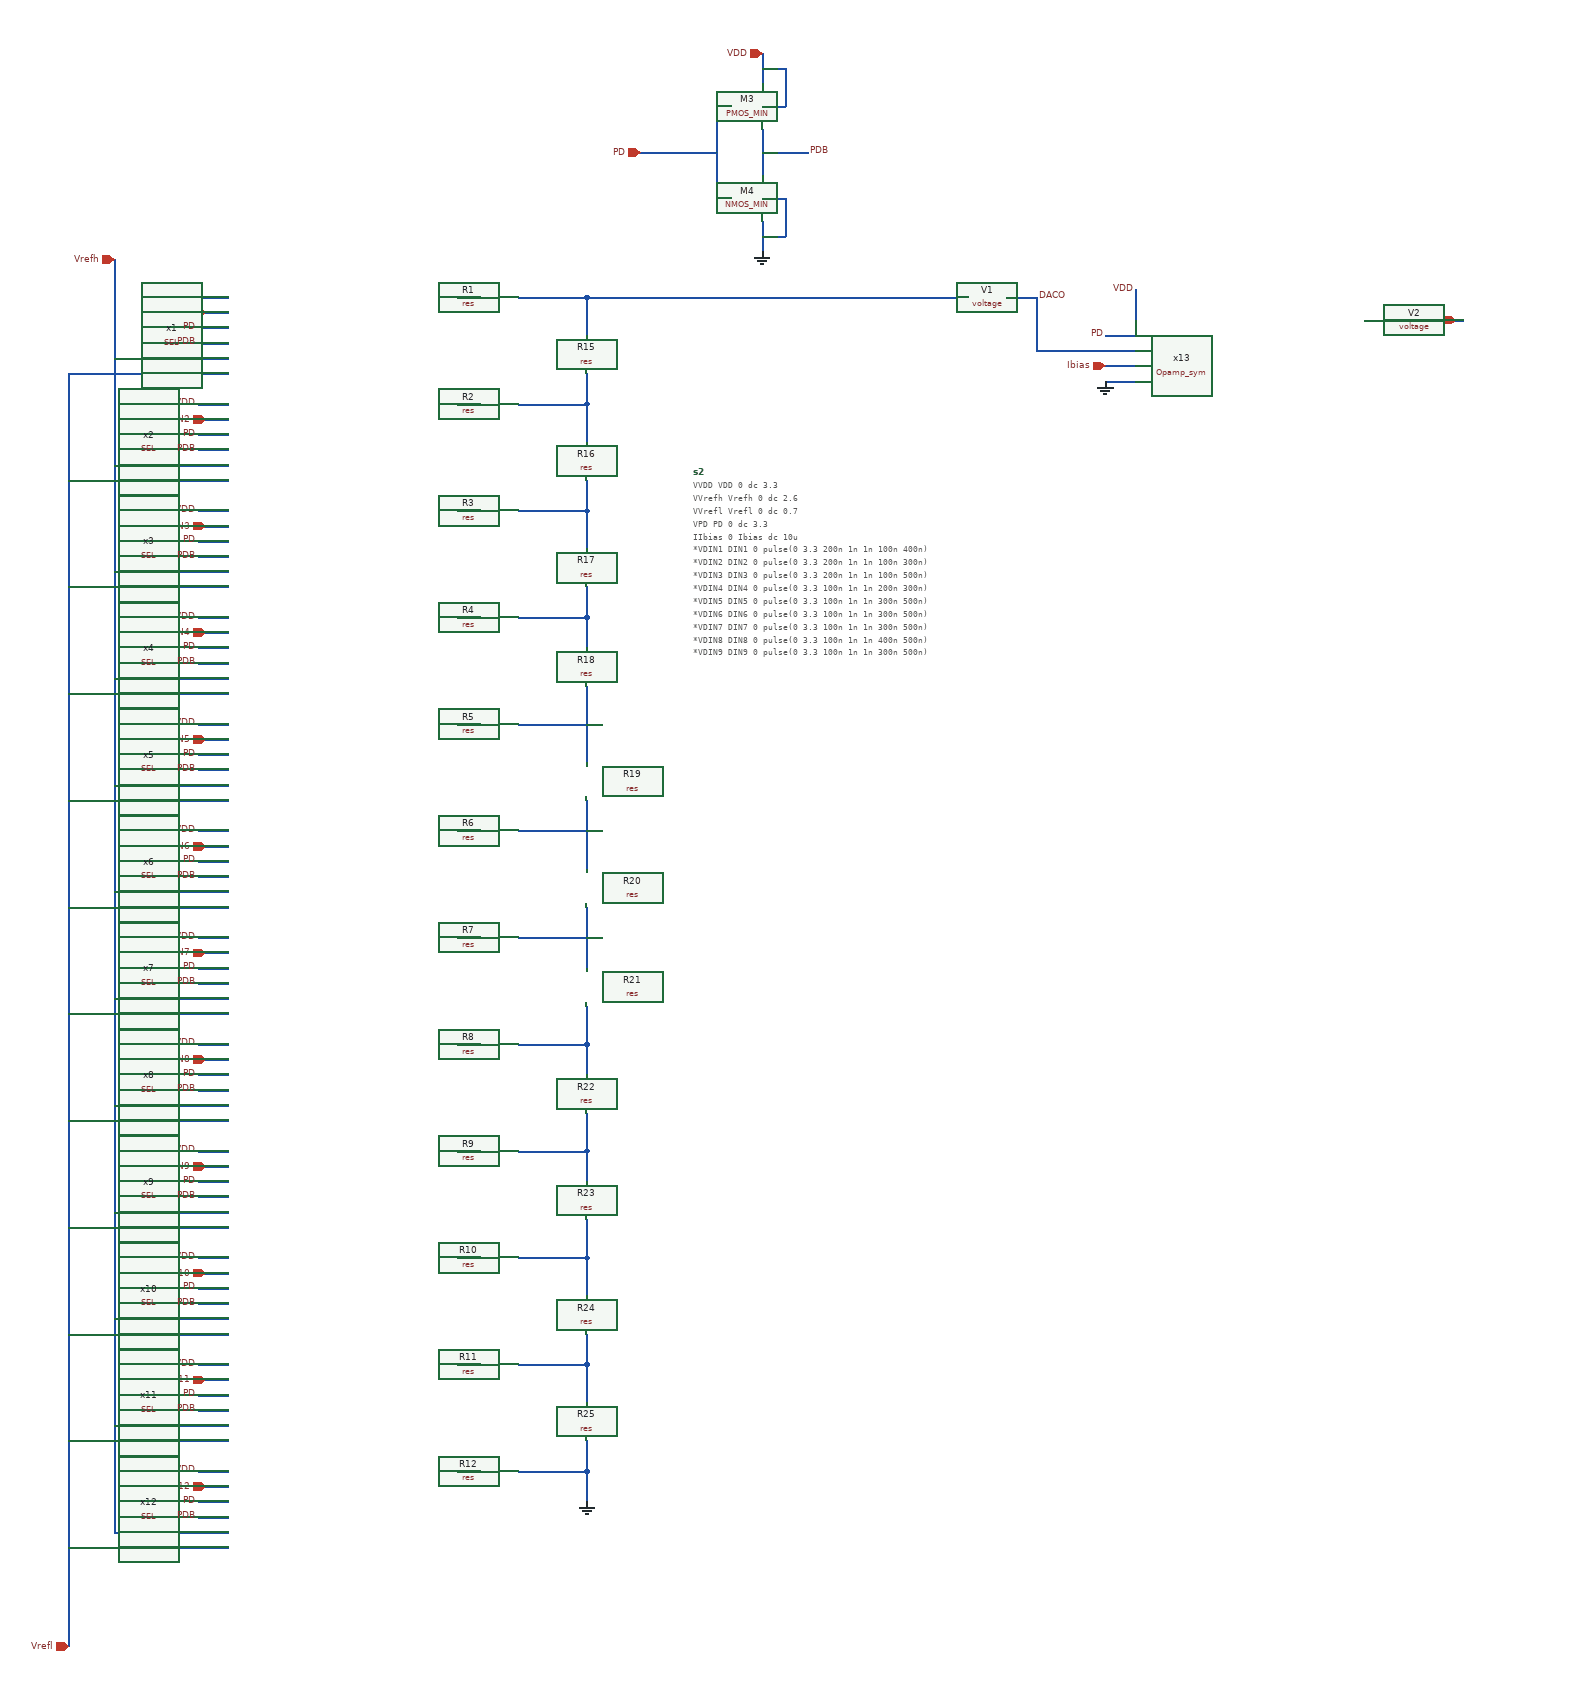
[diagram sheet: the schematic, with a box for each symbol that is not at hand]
v {xschem version=3.4.8RC file_version=1.3}
G {}
K {}
V {}
S {}
F {}
E {}
N 50 -100 140 -100 {lab=#net1}
N 50 40 140 40 {lab=#net2}
N -30 -100 -0 -100 {lab=#net3}
N -30 40 0 40 {lab=#net4}
N -30 180 0 180 {lab=#net5}
N -30 460 0 460 {lab=#net6}
N -30 320 0 320 {lab=#net7}
N -30 600 0 600 {lab=#net8}
N -30 740 0 740 {lab=#net9}
N -30 880 0 880 {lab=#net10}
N -30 1020 0 1020 {lab=#net11}
N -30 1160 0 1160 {lab=#net12}
N -30 1300 0 1300 {lab=#net13}
N -30 1440 0 1440 {lab=#net14}
N -480 -60 -480 1220 {lab=Vrefh}
N -480 1100 -340 1100 {lab=Vrefh}
N -480 260 -340 260 {lab=Vrefh}
N -540 1120 -340 1120 {lab=Vrefl}
N -540 280 -340 280 {lab=Vrefl}
N 140 -100 280 -100 {lab=#net1}
N -360 -80 -330 -80 {lab=DIN1}
N -360 60 -330 60 {lab=DIN2}
N -360 200 -330 200 {lab=DIN3}
N -360 340 -330 340 {lab=DIN4}
N -360 480 -330 480 {lab=DIN5}
N -360 620 -330 620 {lab=DIN6}
N -360 760 -330 760 {lab=DIN7}
N -360 900 -330 900 {lab=DIN8}
N -360 1040 -330 1040 {lab=DIN9}
N -360 1180 -330 1180 {lab=DIN10}
N -360 1320 -330 1320 {lab=DIN11}
N -360 1460 -330 1460 {lab=DIN12}
N 140 -100 140 -70 {lab=#net1}
N 50 180 140 180 {lab=#net15}
N 50 320 140 320 {lab=#net16}
N 50 460 140 460 {lab=#net17}
N 140 440 140 470 {lab=#net17}
N 50 600 140 600 {lab=#net18}
N 50 740 140 740 {lab=#net19}
N 140 470 140 510 {lab=#net17}
N 140 560 140 590 {lab=#net18}
N 140 590 140 620 {lab=#net18}
N 140 710 140 750 {lab=#net19}
N 50 880 140 880 {lab=#net20}
N 50 1160 130 1160 {lab=#net21}
N 50 1300 130 1300 {lab=#net22}
N 130 1300 140 1300 {lab=#net22}
N 50 1440 140 1440 {lab=GND}
N 140 1300 140 1340 {lab=#net22}
N 140 1410 140 1440 {lab=GND}
N 140 1440 140 1480 {lab=GND}
N 370 -200 370 -160 {lab=GND}
N 370 -230 400 -230 {lab=GND}
N 400 -230 400 -180 {lab=GND}
N 370 -180 400 -180 {lab=GND}
N 370 -320 370 -260 {lab=PDB}
N 370 -290 410 -290 {lab=PDB}
N 310 -350 330 -350 {lab=PD}
N 310 -350 310 -230 {lab=PD}
N 310 -230 330 -230 {lab=PD}
N 210 -290 310 -290 {lab=PD}
N 370 -420 370 -380 {lab=VDD}
N 370 -400 400 -400 {lab=VDD}
N 400 -400 400 -350 {lab=VDD}
N 370 -350 400 -350 {lab=VDD}
N -370 -100 -330 -100 {lab=VDD}
N -480 -150 -480 -60 {lab=Vrefh}
N -370 1440 -330 1440 {lab=VDD}
N -370 1300 -330 1300 {lab=VDD}
N -370 1160 -330 1160 {lab=VDD}
N -370 1020 -330 1020 {lab=VDD}
N -370 880 -330 880 {lab=VDD}
N -370 740 -330 740 {lab=VDD}
N -370 600 -330 600 {lab=VDD}
N -370 460 -330 460 {lab=VDD}
N -370 320 -330 320 {lab=VDD}
N -370 180 -330 180 {lab=VDD}
N -370 40 -330 40 {lab=VDD}
N -540 110 -540 1330 {lab=Vrefl}
N 1160 -70 1210 -70 {lab=#net23}
N 860 -110 860 -70 {lab=VDD}
N 820 -10 860 -10 {lab=Ibias}
N 820 10 860 10 {lab=GND}
N 820 -50 860 -50 {lab=PD}
N 280 -100 360 -100 {lab=#net1}
N 410 -290 430 -290 {lab=PDB}
N 770 -30 860 -30 {lab=DACO}
N 690 -100 730 -100 {lab=DACO}
N 1260 -70 1290 -70 {lab=OUT}
N 360 -100 430 -100 {lab=#net1}
N -540 1370 -540 1440 {lab=Vrefl}
N -540 1330 -540 1370 {lab=Vrefl}
N -370 -60 -330 -60 {lab=PD}
N -370 -40 -330 -40 {lab=PDB}
N -480 -20 -330 -20 {lab=Vrefh}
N -540 -0 -330 0 {lab=Vrefl}
N -540 0 -540 110 {lab=Vrefl}
N -370 80 -330 80 {lab=PD}
N -370 100 -330 100 {lab=PDB}
N -480 120 -330 120 {lab=Vrefh}
N -540 140 -330 140 {lab=Vrefl}
N -370 220 -330 220 {lab=PD}
N -370 240 -330 240 {lab=PDB}
N -340 260 -330 260 {lab=Vrefh}
N -340 280 -330 280 {lab=Vrefl}
N -370 360 -330 360 {lab=PD}
N -370 380 -330 380 {lab=PDB}
N -480 400 -330 400 {lab=Vrefh}
N -540 420 -330 420 {lab=Vrefl}
N -370 500 -330 500 {lab=PD}
N -370 520 -330 520 {lab=PDB}
N -480 540 -330 540 {lab=Vrefh}
N -540 560 -330 560 {lab=Vrefl}
N -370 640 -330 640 {lab=PD}
N -370 660 -330 660 {lab=PDB}
N -370 780 -330 780 {lab=PD}
N -370 800 -330 800 {lab=PDB}
N -370 920 -330 920 {lab=PD}
N -370 940 -330 940 {lab=PDB}
N -340 1100 -330 1100 {lab=Vrefh}
N -340 1120 -330 1120 {lab=Vrefl}
N -540 1440 -540 1630 {lab=Vrefl}
N -480 1220 -480 1520 {lab=Vrefh}
N -480 1520 -330 1520 {lab=Vrefh}
N -540 1540 -330 1540 {lab=Vrefl}
N -540 1400 -330 1400 {lab=Vrefl}
N -480 1380 -330 1380 {lab=Vrefh}
N -540 1260 -330 1260 {lab=Vrefl}
N -480 1240 -330 1240 {lab=Vrefh}
N -540 980 -330 980 {lab=Vrefl}
N -480 960 -330 960 {lab=Vrefh}
N -540 840 -330 840 {lab=Vrefl}
N -480 820 -330 820 {lab=Vrefh}
N -540 700 -330 700 {lab=Vrefl}
N -480 680 -330 680 {lab=Vrefh}
N -370 1060 -330 1060 {lab=PD}
N -370 1080 -330 1080 {lab=PDB}
N -370 1200 -330 1200 {lab=PD}
N -370 1220 -330 1220 {lab=PDB}
N -370 1340 -330 1340 {lab=PD}
N -370 1360 -330 1360 {lab=PDB}
N -370 1480 -330 1480 {lab=PD}
N -370 1500 -330 1500 {lab=PDB}
N 140 1340 140 1350 {lab=#net22}
N 140 1400 140 1410 {lab=GND}
N 140 -70 140 -50 {lab=#net1}
N 140 0 140 40 {lab=#net2}
N 140 1260 140 1300 {lab=#net22}
N 130 1160 140 1160 {lab=#net21}
N 140 1160 140 1210 {lab=#net21}
N 50 1020 140 1020 {lab=#net24}
N 140 1020 140 1060 {lab=#net24}
N 140 1110 140 1160 {lab=#net21}
N 140 970 140 1020 {lab=#net24}
N 140 880 140 920 {lab=#net20}
N 140 830 140 880 {lab=#net20}
N 140 750 140 780 {lab=#net19}
N 140 700 140 710 {lab=#net19}
N 140 620 140 650 {lab=#net18}
N 140 410 140 440 {lab=#net17}
N 140 320 140 360 {lab=#net16}
N 140 180 140 230 {lab=#net15}
N 140 280 140 320 {lab=#net16}
N 140 40 140 90 {lab=#net2}
N 140 140 140 180 {lab=#net15}
N -540 1630 -540 1670 {lab=Vrefl}
N 430 -100 600 -100 {lab=#net1}
N 600 -100 640 -100 {lab=#net1}
N 730 -100 730 -70 {lab=DACO}
N 730 -30 770 -30 {lab=DACO}
N 730 -70 730 -30 {lab=DACO}
C {res.sym} 60 -110 1 0 {name=R1
value=400k
footprint=1206
device=resistor
m=1}
C {res.sym} 130 -60 0 0 {name=R15
value=200k
footprint=1206
device=resistor
m=1}
C {ipin.sym} -480 -150 1 0 {name=p1 lab=Vrefh}
C {ipin.sym} -540 1670 3 0 {name=p2 lab=Vrefl}
C {iopin.sym} 1280 -70 0 0 {name=p3 lab=OUT}
C {ipin.sym} -360 -80 0 0 {name=p4 lab=DIN1}
C {ipin.sym} -360 60 0 0 {name=p6 lab=DIN2}
C {ipin.sym} -360 200 0 0 {name=p7 lab=DIN3}
C {ipin.sym} -360 340 0 0 {name=p8 lab=DIN4}
C {ipin.sym} -360 480 0 0 {name=p9 lab=DIN5}
C {ipin.sym} -360 620 0 0 {name=p10 lab=DIN6}
C {ipin.sym} -360 760 0 0 {name=p11 lab=DIN7}
C {ipin.sym} -360 900 0 0 {name=p12 lab=DIN8}
C {ipin.sym} -360 1040 0 0 {name=p13 lab=DIN9}
C {ipin.sym} -360 1180 0 0 {name=p14 lab=DIN10}
C {ipin.sym} -360 1320 0 0 {name=p15 lab=DIN11}
C {ipin.sym} -360 1460 0 0 {name=p16 lab=DIN12}
C {code_shown.sym} 280 130 0 0 {name=s2 only_toplevel=false value=
"
VVDD VDD 0 dc 3.3
VVrefh Vrefh 0 dc 2.6
VVrefl Vrefl 0 dc 0.7
VPD PD 0 dc 3.3
IIbias 0 Ibias dc 10u

*VDIN1 DIN1 0 pulse(0 3.3 200n 1n 1n 100n 400n)
*VDIN2 DIN2 0 pulse(0 3.3 200n 1n 1n 100n 300n)
*VDIN3 DIN3 0 pulse(0 3.3 200n 1n 1n 100n 500n)
*VDIN4 DIN4 0 pulse(0 3.3 100n 1n 1n 200n 300n)
*VDIN5 DIN5 0 pulse(0 3.3 100n 1n 1n 300n 500n)
*VDIN6 DIN6 0 pulse(0 3.3 100n 1n 1n 300n 500n)
*VDIN7 DIN7 0 pulse(0 3.3 100n 1n 1n 300n 500n)
*VDIN8 DIN8 0 pulse(0 3.3 100n 1n 1n 400n 500n)
*VDIN9 DIN9 0 pulse(0 3.3 100n 1n 1n 300n 500n)
*VDIN10 DIN10 0 pulse(0 3.3 100n 1n 1n 300n 500n)
*VDIN11 DIN11 0 pulse(0 3.3 100n 1n 1n 300n 500n)
*VDIN12 DIN12 0 pulse(0 3.3 100n 1n 1n 400n 500n)

*DNL-INL
VDIN1 DIN1 0 pulse(3.3 0 100n 1n 1n 204800n 409600n)
VDIN2 DIN2 0 pulse(3.3 0 100n 1n 1n 102400n 204800n)
VDIN3 DIN3 0 pulse(3.3 0 100n 1n 1n 51200n 102400n)
VDIN4 DIN4 0 pulse(3.3 0 100n 1n 1n 25600n 51200n)
VDIN5 DIN5 0 pulse(3.3 0 100n 1n 1n 12800n 25600n)
VDIN6 DIN6 0 pulse(3.3 0 100n 1n 1n 6400n 12800n)
VDIN7 DIN7 0 pulse(3.3 0 100n 1n 1n 3200n 6400n)
VDIN8 DIN8 0 pulse(3.3 0 100n 1n 1n 1600n 3200n)
VDIN9 DIN9 0 pulse(3.3 0 100n 1n 1n 800n 1600n)
VDIN10 DIN10 0 pulse(3.3 0 100n 1n 1n 400n 800n)
VDIN11 DIN11 0 pulse(3.3 0 100n 1n 1n 200n 400n)
VDIN12 DIN12 0 pulse(3.3 0 100n 1n 1n 100n 200n)


.meas tran IDDA AVG I(V1) from=200n to=300n
.meas tran IDDM MAX I(V1) from=200n to=300n
.meas tran IDDMI MIN I(V1) from=200n to=300n 
.meas tran IAVG AVG I(V2) from=200n to=300n
.meas tran IDDS MAX I(V2) from=200n to=300n
.meas tran 12h000 FIND V(OUT) AT=90n
*.meas tran 12h1ff FIND V(DACO) AT=190n
.meas tran 12hfff FIND V(OUT) AT=290n
*.meas tran 12h0ff FIND V(DACO) AT=390n
*.meas tran 12h111 FIND V(DACO) AT=490n
*.meas tran IAVG2 AVG I(V2) from=100.1n to=200n
*.meas tran gain1 AVG V(DACO)
*.meas tran gain2 AVG V(OUT)

.include /home/raidonn/LRCircuit/spicemodel/ocs65_stl_n3_typ.para
.include /home/raidonn/LRCircuit/spicemodel/ocs65_stl_p3_typ.para

.control
save all
set filetype=ascii
set wr_singlescale
set wr_vecnames
option numdgt=5
tran 100n 410u 90n
*tran 1n 500n
plot V(DACO) V(OUT)
plot V(OUT)
*plot I(V1)
*plot I(V2)

linearize V(DACO) V(OUT)

write "RDAC_12bit.raw"
wrdata "RDAC_INL_DNL_amp.csv" V(DACO) V(OUT)

.endc"
}
C {res.sym} 60 30 1 0 {name=R2
value=400k
footprint=1206
device=resistor
m=1}
C {res.sym} 60 170 1 0 {name=R3
value=400k
footprint=1206
device=resistor
m=1}
C {res.sym} 60 310 1 0 {name=R4
value=400k
footprint=1206
device=resistor
m=1}
C {res.sym} 60 450 1 0 {name=R5
value=400k
footprint=1206
device=resistor
m=1}
C {res.sym} 60 590 1 0 {name=R6
value=400k
footprint=1206
device=resistor
m=1}
C {res.sym} 60 730 1 0 {name=R7
value=400k
footprint=1206
device=resistor
m=1}
C {res.sym} 60 870 1 0 {name=R8
value=400k
footprint=1206
device=resistor
m=1}
C {res.sym} 60 1010 1 0 {name=R9
value=400k
footprint=1206
device=resistor
m=1}
C {res.sym} 60 1150 1 0 {name=R10
value=400k
footprint=1206
device=resistor
m=1}
C {res.sym} 60 1290 1 0 {name=R11
value=400k
footprint=1206
device=resistor
m=1}
C {res.sym} 60 1430 1 0 {name=R12
value=400k
footprint=1206
device=resistor
m=1}
C {res.sym} 130 80 0 0 {name=R16
value=200k
footprint=1206
device=resistor
m=1}
C {res.sym} 130 220 0 0 {name=R17
value=200k
footprint=1206
device=resistor
m=1}
C {res.sym} 130 350 0 0 {name=R18
value=200k
footprint=1206
device=resistor
m=1}
C {res.sym} 130 500 0 0 {name=R19
value=200k
footprint=1206
device=resistor
m=1}
C {res.sym} 130 640 0 0 {name=R20
value=200k
footprint=1206
device=resistor
m=1}
C {res.sym} 130 770 0 0 {name=R21
value=200k
footprint=1206
device=resistor
m=1}
C {res.sym} 130 910 0 0 {name=R22
value=200k
footprint=1206
device=resistor
m=1}
C {res.sym} 130 1050 0 0 {name=R23
value=200k
footprint=1206
device=resistor
m=1}
C {res.sym} 130 1200 0 0 {name=R24
value=200k
footprint=1206
device=resistor
m=1}
C {res.sym} 130 1340 0 0 {name=R25
value=200k
footprint=1206
device=resistor
m=1}
C {gnd.sym} 140 1480 0 0 {name=l1 lab=GND}
C {PMOS_MIN.sym} 330 -350 0 0 {name=M3 model=p3.0 w=3.5u l=0.35u as=0 ps=0 ad=0 pd=0 m=1}
C {NMOS_MIN.sym} 330 -230 0 0 {name=M4 model=n3.0 w=3.5u l=0.35u as=0 ps=0 ad=0 pd=0 m=1}
C {ipin.sym} 210 -290 0 0 {name=p5 lab=PD}
C {gnd.sym} 370 -160 0 0 {name=l2 lab=GND}
C {ipin.sym} 370 -420 1 0 {name=p19 lab=VDD}
C {lab_pin.sym} -370 -100 0 0 {name=l5 sig_type=std_logic lab=VDD}
C {lab_pin.sym} -370 1440 0 0 {name=l8 sig_type=std_logic lab=VDD}
C {lab_pin.sym} -370 1300 0 0 {name=l9 sig_type=std_logic lab=VDD}
C {lab_pin.sym} -370 1160 0 0 {name=l10 sig_type=std_logic lab=VDD}
C {lab_pin.sym} -370 1020 0 0 {name=l11 sig_type=std_logic lab=VDD}
C {lab_pin.sym} -370 880 0 0 {name=l12 sig_type=std_logic lab=VDD}
C {lab_pin.sym} -370 740 0 0 {name=l13 sig_type=std_logic lab=VDD}
C {lab_pin.sym} -370 600 0 0 {name=l14 sig_type=std_logic lab=VDD}
C {lab_pin.sym} -370 460 0 0 {name=l15 sig_type=std_logic lab=VDD}
C {lab_pin.sym} -370 320 0 0 {name=l16 sig_type=std_logic lab=VDD}
C {lab_pin.sym} -370 180 0 0 {name=l17 sig_type=std_logic lab=VDD}
C {lab_pin.sym} -370 40 0 0 {name=l18 sig_type=std_logic lab=VDD}
C {lab_pin.sym} 860 -110 1 0 {name=l19 sig_type=std_logic lab=VDD}
C {ipin.sym} 820 -10 0 0 {name=p20 lab=Ibias}
C {gnd.sym} 820 10 0 0 {name=l20 lab=GND}
C {lab_pin.sym} 820 -50 0 0 {name=l21 sig_type=std_logic lab=PD}
C {lab_pin.sym} 430 -290 2 0 {name=l24 sig_type=std_logic lab=PDB}
C {voltage.sym} 630 -100 3 0 {name=V1 value=0}
C {/home/raidonn/LRCircuit/work4/origin/SEL.sym} -180 -50 0 0 {name=x1}
C {/home/raidonn/LRCircuit/work4/origin/SEL.sym} -180 90 0 0 {name=x2}
C {/home/raidonn/LRCircuit/work4/origin/SEL.sym} -180 230 0 0 {name=x3}
C {/home/raidonn/LRCircuit/work4/origin/SEL.sym} -180 370 0 0 {name=x4}
C {/home/raidonn/LRCircuit/work4/origin/SEL.sym} -180 510 0 0 {name=x5}
C {/home/raidonn/LRCircuit/work4/origin/SEL.sym} -180 650 0 0 {name=x6}
C {/home/raidonn/LRCircuit/work4/origin/SEL.sym} -180 790 0 0 {name=x7}
C {/home/raidonn/LRCircuit/work4/origin/SEL.sym} -180 930 0 0 {name=x8}
C {/home/raidonn/LRCircuit/work4/origin/SEL.sym} -180 1070 0 0 {name=x9}
C {/home/raidonn/LRCircuit/work4/origin/SEL.sym} -180 1210 0 0 {name=x10}
C {/home/raidonn/LRCircuit/work4/origin/SEL.sym} -180 1350 0 0 {name=x11}
C {/home/raidonn/LRCircuit/work4/origin/SEL.sym} -180 1490 0 0 {name=x12}
C {/home/raidonn/LRCircuit/work4/origin/Opamp_sym.sym} 1010 -30 0 0 {name=x13}
C {voltage.sym} 1200 -70 3 0 {name=V2 value=0}
C {lab_pin.sym} -370 -60 0 0 {name=l3 sig_type=std_logic lab=PD}
C {lab_pin.sym} -370 -40 0 0 {name=l6 sig_type=std_logic lab=PDB}
C {lab_pin.sym} -370 80 0 0 {name=l7 sig_type=std_logic lab=PD}
C {lab_pin.sym} -370 100 0 0 {name=l22 sig_type=std_logic lab=PDB}
C {lab_pin.sym} -370 220 0 0 {name=l23 sig_type=std_logic lab=PD}
C {lab_pin.sym} -370 240 0 0 {name=l25 sig_type=std_logic lab=PDB}
C {lab_pin.sym} -370 360 0 0 {name=l26 sig_type=std_logic lab=PD}
C {lab_pin.sym} -370 380 0 0 {name=l27 sig_type=std_logic lab=PDB}
C {lab_pin.sym} -370 500 0 0 {name=l28 sig_type=std_logic lab=PD}
C {lab_pin.sym} -370 520 0 0 {name=l29 sig_type=std_logic lab=PDB}
C {lab_pin.sym} -370 640 0 0 {name=l30 sig_type=std_logic lab=PD}
C {lab_pin.sym} -370 660 0 0 {name=l31 sig_type=std_logic lab=PDB}
C {lab_pin.sym} -370 780 0 0 {name=l32 sig_type=std_logic lab=PD}
C {lab_pin.sym} -370 800 0 0 {name=l33 sig_type=std_logic lab=PDB}
C {lab_pin.sym} -370 920 0 0 {name=l34 sig_type=std_logic lab=PD}
C {lab_pin.sym} -370 940 0 0 {name=l35 sig_type=std_logic lab=PDB}
C {lab_pin.sym} -370 1060 0 0 {name=l36 sig_type=std_logic lab=PD}
C {lab_pin.sym} -370 1080 0 0 {name=l37 sig_type=std_logic lab=PDB}
C {lab_pin.sym} -370 1200 0 0 {name=l38 sig_type=std_logic lab=PD}
C {lab_pin.sym} -370 1220 0 0 {name=l39 sig_type=std_logic lab=PDB}
C {lab_pin.sym} -370 1340 0 0 {name=l40 sig_type=std_logic lab=PD}
C {lab_pin.sym} -370 1360 0 0 {name=l41 sig_type=std_logic lab=PDB}
C {lab_pin.sym} -370 1480 0 0 {name=l42 sig_type=std_logic lab=PD}
C {lab_pin.sym} -370 1500 0 0 {name=l43 sig_type=std_logic lab=PDB}
C {lab_pin.sym} 730 -100 2 0 {name=l4 sig_type=std_logic lab=DACO}
